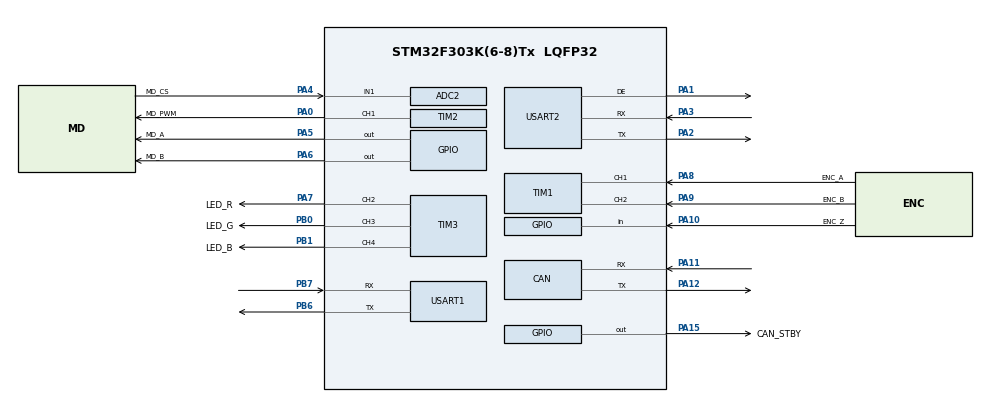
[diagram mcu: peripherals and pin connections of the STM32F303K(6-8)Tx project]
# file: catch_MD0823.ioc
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ADC2.Channel-0\#ChannelRegularConversion=ADC_CHANNEL_1
ADC2.NbrOfConversionFlag=1
ADC2.Offset-0\#ChannelRegularConversion=0
ADC2.OffsetNumber-0\#ChannelRegularConversion=ADC_OFFSET_NONE
ADC2.Rank-0\#ChannelRegularConversion=1
ADC2.SamplingTime-0\#ChannelRegularConversion=ADC_SAMPLETIME_1CYCLE_5
ADC2.SubFamily=STM32F303x8
CAN.CalculateTimeQuantum=2000.0
Mcu.Family=STM32F3
Mcu.Name=STM32F303K(6-8)Tx
Mcu.Package=LQFP32
NVIC.PriorityGroup=NVIC_PRIORITYGROUP_4
PA0.GPIO_Label=MD_PWM
PA0.Signal=S_TIM2_CH1_ETR
PA1.Mode=Hardware Flow Control (RS485)
PA1.Signal=USART2_DE
PA10.GPIO_Label=ENC_Z
PA10.Signal=GPIO_Input
PA11.Mode=Master
PA11.Signal=CAN_RX
PA12.Mode=Master
PA12.Signal=CAN_TX
PA13.Mode=Serial_Wire
PA13.Signal=SYS_JTMS-SWDIO
PA14.Mode=Serial_Wire
PA14.Signal=SYS_JTCK-SWCLK
PA15.GPIO_Label=CAN_STBY
PA15.Signal=GPIO_Output
PA2.Mode=Asynchronous
PA2.Signal=USART2_TX
PA3.Mode=Asynchronous
PA3.Signal=USART2_RX
PA4.GPIO_Label=MD_CS
PA4.Mode=IN1-Single-Ended
PA4.Signal=ADC2_IN1
PA5.GPIO_Label=MD_A
PA5.Signal=GPIO_Output
PA6.GPIO_Label=MD_B
PA6.Signal=GPIO_Output
PA7.GPIO_Label=LED_R
PA7.Signal=S_TIM3_CH2
PA8.GPIO_Label=ENC_A
PA8.Signal=S_TIM1_CH1
PA9.GPIO_Label=ENC_B
PA9.Signal=S_TIM1_CH2
PB0.GPIO_Label=LED_G
PB0.Signal=S_TIM3_CH3
PB1.GPIO_Label=LED_B
PB1.Signal=S_TIM3_CH4
PB6.Mode=Asynchronous
PB6.Signal=USART1_TX
PB7.Mode=Asynchronous
PB7.Signal=USART1_RX
ProjectManager.HeapSize=0x200
ProjectManager.StackSize=0x400
ProjectManager.TargetToolchain=SW4STM32
RCC.AHBFreq_Value=8000000
RCC.APB1Freq_Value=8000000
RCC.APB2Freq_Value=8000000
RCC.CortexFreq_Value=8000000
RCC.HSE_VALUE=8000000
RCC.HSI_VALUE=8000000
RCC.PLLMUL=RCC_PLL_MUL4
RCC.SYSCLKFreq_VALUE=8000000
SH.S_TIM1_CH1.0=TIM1_CH1,Encoder_Interface
SH.S_TIM1_CH2.0=TIM1_CH2,Encoder_Interface
SH.S_TIM2_CH1_ETR.0=TIM2_CH1,PWM Generation1 CH1
SH.S_TIM3_CH2.0=TIM3_CH2,PWM Generation2 CH2
SH.S_TIM3_CH3.0=TIM3_CH3,PWM Generation3 CH3
SH.S_TIM3_CH4.0=TIM3_CH4,PWM Generation4 CH4
TIM2.Channel-PWM\ Generation1\ CH1=TIM_CHANNEL_1
TIM2.Period=999
TIM2.Prescaler=126
TIM3.Channel-PWM\ Generation2\ CH2=TIM_CHANNEL_2
TIM3.Channel-PWM\ Generation3\ CH3=TIM_CHANNEL_3
TIM3.Channel-PWM\ Generation4\ CH4=TIM_CHANNEL_4
USART1.VirtualMode-Asynchronous=VM_ASYNC
USART2.VirtualMode-Asynchronous=VM_ASYNC
USART2.VirtualMode-Hardware\ Flow\ Control\ (RS485)=VM_ASYNC
VP_TIM17_VS_ClockSourceINT.Mode=Enable_Timer
board=custom

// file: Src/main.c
/* USER CODE BEGIN Header */
/**
  ******************************************************************************
  * @file           : main.c
  * @brief          : Main program body
  ******************************************************************************
  * @attention
  *
  * <h2><center>&copy; Copyright (c) 2019 STMicroelectronics.
  * All rights reserved.</center></h2>
  *
  * This software component is licensed by ST under BSD 3-Clause license,
  * the "License"; You may not use this file except in compliance with the
  * License. You may obtain a copy of the License at:
  *                        opensource.org/licenses/BSD-3-Clause
  *
  ******************************************************************************
  */
/* USER CODE END Header */

#include "main.h"

/* USER CODE BEGIN Includes */
#include "struct.h"
#include "motor.h"
#include "encoder.h"
#include "robotstate.h"

/* USER CODE END Includes */

ADC_HandleTypeDef hadc2;

CAN_HandleTypeDef hcan;

TIM_HandleTypeDef htim1;
TIM_HandleTypeDef htim2;
TIM_HandleTypeDef htim3;
TIM_HandleTypeDef htim17;

UART_HandleTypeDef huart1;
UART_HandleTypeDef huart2;

/* USER CODE BEGIN PV */
static char s[255] = {'\0'};
int pwm_result = 0;

//CAN data storage
uint8_t tx[8]; //data which send to "main"
uint8_t rx[8]; //data which receive from "main"
CAN_FilterTypeDef sFilterConfig1;
CAN_TxHeaderTypeDef pHeader1;
CAN_RxHeaderTypeDef pHeader2;
/* USER CODE END PV */

void SystemClock_Config(void);
static void MX_GPIO_Init(void);
static void MX_ADC2_Init(void);
static void MX_CAN_Init(void);
static void MX_TIM1_Init(void);
static void MX_TIM2_Init(void);
static void MX_TIM3_Init(void);
static void MX_TIM17_Init(void);
static void MX_USART1_UART_Init(void);
static void MX_USART2_UART_Init(void);

int main(void)
{

  /* MCU Configuration--------------------------------------------------------*/

  /* Reset of all peripherals, Initializes the Flash interface and the Systick. */
  HAL_Init();

  /* Configure the system clock */
  SystemClock_Config();

  /* Initialize all configured peripherals */
  MX_GPIO_Init();
  MX_ADC2_Init();
  MX_CAN_Init();
  MX_TIM1_Init();
  MX_TIM2_Init();
  MX_TIM3_Init();
  MX_TIM17_Init();
  MX_USART1_UART_Init();
  MX_USART2_UART_Init();
  /* USER CODE BEGIN 2 */
  CoordinateEnable();

  EncEnable();

  HAL_Delay(300);

  pwm_result = TestPos(0.8f);

  HAL_Delay(2000);

  pwm_result = TestPos(-0.8f);

  HAL_Delay(2000);

  CoordinateDisable();
  HAL_Delay(500);

//  CoordinateEnable();
  HAL_TIM_PWM_Start(&htim3,TIM_CHANNEL_2 );

  /* USER CODE END 2 */

  /* Infinite loop */
  /* USER CODE BEGIN WHILE */
  while (1)
  {

	  __HAL_TIM_SET_COMPARE(&htim3, TIM_CHANNEL_2, 	800);
	  HAL_Delay(500);
	  __HAL_TIM_SET_COMPARE(&htim3, TIM_CHANNEL_2, 	200);
	  HAL_Delay(500);

	  /*
	  HAL_GPIO_WritePin(GPIOA, GPIO_PIN_7, GPIO_PIN_SET);
	  HAL_GPIO_WritePin(GPIOB, GPIO_PIN_0, GPIO_PIN_SET);
	  HAL_GPIO_WritePin(GPIOB, GPIO_PIN_1, GPIO_PIN_SET);

//	  HAL_GPIO_WritePin(MOTOR_R_1_PORT, MOTOR_R_1_PIN, GPIO_PIN_RESET);
//	  HAL_GPIO_WritePin(MOTOR_R_2_PORT, MOTOR_R_2_PIN, GPIO_PIN_SET);

	  HAL_Delay(500);
	  HAL_GPIO_WritePin(GPIOA, GPIO_PIN_7, GPIO_PIN_RESET);
	  HAL_GPIO_WritePin(GPIOB, GPIO_PIN_0, GPIO_PIN_RESET);
	  HAL_GPIO_WritePin(GPIOB, GPIO_PIN_1, GPIO_PIN_RESET);

	  HAL_GPIO_WritePin(MOTOR_R_1_PORT, MOTOR_R_1_PIN, GPIO_PIN_SET);
      HAL_GPIO_WritePin(MOTOR_R_2_PORT, MOTOR_R_2_PIN, GPIO_PIN_RESET);

	  HAL_Delay(500);
	  */

	  static int16_t enc1_buf = 0;
	  //receive data(instruction) from "main"
	  if (HAL_CAN_GetRxFifoFillLevel(&hcan,CAN_RX_FIFO0) != 0U)
	  {
	    if (HAL_CAN_GetRxMessage(&hcan, CAN_RX_FIFO0, &pHeader2, rx) != HAL_OK)
	    {
	  	  Error_Handler();
	    }
	  }
//	  rx[0],rx[1]... use for encoder
	  //get measurement data
	  EncGetData(&enc1_buf);
//	  enc1_buf = -10;
	  sprintf(s, "Enc1: %d \r\n", (int)enc1_buf);
	  HAL_UART_Transmit(&huart2,(uint8_t *)s, strlen(s), 100);
	  //send data to "main"
	  tx[0] = (int)enc1_buf;
	  if (HAL_CAN_AddTxMessage(&hcan, &pHeader1, tx, (uint32_t *)CAN_TX_MAILBOX0) != HAL_OK)
	  {
	    Error_Handler();
	  }
	  HAL_Delay(500);

    /* USER CODE END WHILE */

  }
}

void SystemClock_Config(void)
{
  RCC_OscInitTypeDef RCC_OscInitStruct = {0};
  RCC_ClkInitTypeDef RCC_ClkInitStruct = {0};
  RCC_PeriphCLKInitTypeDef PeriphClkInit = {0};

  /** Initializes the CPU, AHB and APB busses clocks
  */
  RCC_OscInitStruct.OscillatorType = RCC_OSCILLATORTYPE_HSI;
  RCC_OscInitStruct.HSIState = RCC_HSI_ON;
  RCC_OscInitStruct.HSICalibrationValue = RCC_HSICALIBRATION_DEFAULT;
  RCC_OscInitStruct.PLL.PLLState = RCC_PLL_ON;
  RCC_OscInitStruct.PLL.PLLSource = RCC_PLLSOURCE_HSI;
  RCC_OscInitStruct.PLL.PLLMUL = RCC_PLL_MUL8;
  if (HAL_RCC_OscConfig(&RCC_OscInitStruct) != HAL_OK)
  {
    Error_Handler();
  }
  /** Initializes the CPU, AHB and APB busses clocks
  */
  RCC_ClkInitStruct.ClockType = RCC_CLOCKTYPE_HCLK|RCC_CLOCKTYPE_SYSCLK
                              |RCC_CLOCKTYPE_PCLK1|RCC_CLOCKTYPE_PCLK2;
  RCC_ClkInitStruct.SYSCLKSource = RCC_SYSCLKSOURCE_PLLCLK;
  RCC_ClkInitStruct.AHBCLKDivider = RCC_SYSCLK_DIV1;
  RCC_ClkInitStruct.APB1CLKDivider = RCC_HCLK_DIV1;
  RCC_ClkInitStruct.APB2CLKDivider = RCC_HCLK_DIV1;

  if (HAL_RCC_ClockConfig(&RCC_ClkInitStruct, FLASH_LATENCY_1) != HAL_OK)
  {
    Error_Handler();
  }
  PeriphClkInit.PeriphClockSelection = RCC_PERIPHCLK_USART1|RCC_PERIPHCLK_TIM1
                              |RCC_PERIPHCLK_ADC12;
  PeriphClkInit.Usart1ClockSelection = RCC_USART1CLKSOURCE_PCLK1;
  PeriphClkInit.Adc12ClockSelection = RCC_ADC12PLLCLK_DIV1;
  PeriphClkInit.Tim1ClockSelection = RCC_TIM1CLK_HCLK;
  if (HAL_RCCEx_PeriphCLKConfig(&PeriphClkInit) != HAL_OK)
  {
    Error_Handler();
  }
}

static void MX_ADC2_Init(void)
{

  ADC_ChannelConfTypeDef sConfig = {0};

  /** Common config
  */
  hadc2.Instance = ADC2;
  hadc2.Init.ClockPrescaler = ADC_CLOCK_ASYNC_DIV1;
  hadc2.Init.Resolution = ADC_RESOLUTION_12B;
  hadc2.Init.ScanConvMode = ADC_SCAN_DISABLE;
  hadc2.Init.ContinuousConvMode = DISABLE;
  hadc2.Init.DiscontinuousConvMode = DISABLE;
  hadc2.Init.ExternalTrigConvEdge = ADC_EXTERNALTRIGCONVEDGE_NONE;
  hadc2.Init.ExternalTrigConv = ADC_SOFTWARE_START;
  hadc2.Init.DataAlign = ADC_DATAALIGN_RIGHT;
  hadc2.Init.NbrOfConversion = 1;
  hadc2.Init.DMAContinuousRequests = DISABLE;
  hadc2.Init.EOCSelection = ADC_EOC_SINGLE_CONV;
  hadc2.Init.LowPowerAutoWait = DISABLE;
  hadc2.Init.Overrun = ADC_OVR_DATA_OVERWRITTEN;
  if (HAL_ADC_Init(&hadc2) != HAL_OK)
  {
    Error_Handler();
  }
  /** Configure Regular Channel
  */
  sConfig.Channel = ADC_CHANNEL_1;
  sConfig.Rank = ADC_REGULAR_RANK_1;
  sConfig.SingleDiff = ADC_SINGLE_ENDED;
  sConfig.SamplingTime = ADC_SAMPLETIME_1CYCLE_5;
  sConfig.OffsetNumber = ADC_OFFSET_NONE;
  sConfig.Offset = 0;
  if (HAL_ADC_ConfigChannel(&hadc2, &sConfig) != HAL_OK)
  {
    Error_Handler();
  }

}

static void MX_CAN_Init(void)
{

  hcan.Instance = CAN;
  hcan.Init.Prescaler = 16;
  hcan.Init.Mode = CAN_MODE_NORMAL;
  hcan.Init.SyncJumpWidth = CAN_SJW_1TQ;
  hcan.Init.TimeSeg1 = CAN_BS1_1TQ;
  hcan.Init.TimeSeg2 = CAN_BS2_1TQ;
  hcan.Init.TimeTriggeredMode = DISABLE;
  hcan.Init.AutoBusOff = DISABLE;
  hcan.Init.AutoWakeUp = DISABLE;
  hcan.Init.AutoRetransmission = DISABLE;
  hcan.Init.ReceiveFifoLocked = DISABLE;
  hcan.Init.TransmitFifoPriority = DISABLE;
  if (HAL_CAN_Init(&hcan) != HAL_OK)
  {
    Error_Handler();
  }
  /* USER CODE BEGIN CAN_Init 2 */

  sFilterConfig1.FilterIdHigh = 0x0020;//32(this_slave_stdId=1)**(all_slave_stdId is 1~8)
  sFilterConfig1.FilterIdLow = 0x0000;
  sFilterConfig1.FilterMaskIdHigh = 0xFFE0;//"stdId=1" only accept
  sFilterConfig1.FilterMaskIdLow = 0x0004; //CAN_ID_STD accept
  sFilterConfig1.FilterMode = CAN_FILTERMODE_IDMASK;
  sFilterConfig1.FilterScale = CAN_FILTERSCALE_32BIT;
  sFilterConfig1.FilterFIFOAssignment = 0;
  sFilterConfig1.FilterActivation = ENABLE;
  if (HAL_CAN_ConfigFilter(&hcan, &sFilterConfig1) != HAL_OK)
    {
      // Filter configuration Error
      Error_Handler();
    }
  pHeader1.IDE = CAN_ID_STD;//NOT extend
  pHeader1.RTR = CAN_RTR_DATA;
  pHeader1.StdId = 0x10;//main stdId is 16 **(all main is 16~23)
  pHeader1.ExtId = 0x10;
  pHeader1.DLC = 1;//number of tx data

  /* USER CODE END CAN_Init 2 */

}

static void MX_TIM1_Init(void)
{

  TIM_Encoder_InitTypeDef sConfig = {0};
  TIM_MasterConfigTypeDef sMasterConfig = {0};

  htim1.Instance = TIM1;
  htim1.Init.Prescaler = 0;
  htim1.Init.CounterMode = TIM_COUNTERMODE_UP;
  htim1.Init.Period = 0;
  htim1.Init.ClockDivision = TIM_CLOCKDIVISION_DIV1;
  htim1.Init.RepetitionCounter = 0;
  htim1.Init.AutoReloadPreload = TIM_AUTORELOAD_PRELOAD_DISABLE;
  sConfig.EncoderMode = TIM_ENCODERMODE_TI1;
  sConfig.IC1Polarity = TIM_ICPOLARITY_RISING;
  sConfig.IC1Selection = TIM_ICSELECTION_DIRECTTI;
  sConfig.IC1Prescaler = TIM_ICPSC_DIV1;
  sConfig.IC1Filter = 0;
  sConfig.IC2Polarity = TIM_ICPOLARITY_RISING;
  sConfig.IC2Selection = TIM_ICSELECTION_DIRECTTI;
  sConfig.IC2Prescaler = TIM_ICPSC_DIV1;
  sConfig.IC2Filter = 0;
  if (HAL_TIM_Encoder_Init(&htim1, &sConfig) != HAL_OK)
  {
    Error_Handler();
  }
  sMasterConfig.MasterOutputTrigger = TIM_TRGO_RESET;
  sMasterConfig.MasterOutputTrigger2 = TIM_TRGO2_RESET;
  sMasterConfig.MasterSlaveMode = TIM_MASTERSLAVEMODE_DISABLE;
  if (HAL_TIMEx_MasterConfigSynchronization(&htim1, &sMasterConfig) != HAL_OK)
  {
    Error_Handler();
  }

}

static void MX_TIM2_Init(void)
{

  TIM_MasterConfigTypeDef sMasterConfig = {0};
  TIM_OC_InitTypeDef sConfigOC = {0};

  htim2.Instance = TIM2;
  htim2.Init.Prescaler = 0;
  htim2.Init.CounterMode = TIM_COUNTERMODE_UP;
  htim2.Init.Period = 0;
  htim2.Init.ClockDivision = TIM_CLOCKDIVISION_DIV1;
  htim2.Init.AutoReloadPreload = TIM_AUTORELOAD_PRELOAD_DISABLE;
  if (HAL_TIM_PWM_Init(&htim2) != HAL_OK)
  {
    Error_Handler();
  }
  sMasterConfig.MasterOutputTrigger = TIM_TRGO_RESET;
  sMasterConfig.MasterSlaveMode = TIM_MASTERSLAVEMODE_DISABLE;
  if (HAL_TIMEx_MasterConfigSynchronization(&htim2, &sMasterConfig) != HAL_OK)
  {
    Error_Handler();
  }
  sConfigOC.OCMode = TIM_OCMODE_PWM1;
  sConfigOC.Pulse = 0;
  sConfigOC.OCPolarity = TIM_OCPOLARITY_HIGH;
  sConfigOC.OCFastMode = TIM_OCFAST_DISABLE;
  if (HAL_TIM_PWM_ConfigChannel(&htim2, &sConfigOC, TIM_CHANNEL_1) != HAL_OK)
  {
    Error_Handler();
  }
  HAL_TIM_MspPostInit(&htim2);

}

static void MX_TIM3_Init(void)
{

  TIM_MasterConfigTypeDef sMasterConfig = {0};
  TIM_OC_InitTypeDef sConfigOC = {0};

  htim3.Instance = TIM3;
  htim3.Init.Prescaler = 0;
  htim3.Init.CounterMode = TIM_COUNTERMODE_UP;
  htim3.Init.Period = 0;
  htim3.Init.ClockDivision = TIM_CLOCKDIVISION_DIV1;
  htim3.Init.AutoReloadPreload = TIM_AUTORELOAD_PRELOAD_DISABLE;
  if (HAL_TIM_PWM_Init(&htim3) != HAL_OK)
  {
    Error_Handler();
  }
  sMasterConfig.MasterOutputTrigger = TIM_TRGO_RESET;
  sMasterConfig.MasterSlaveMode = TIM_MASTERSLAVEMODE_DISABLE;
  if (HAL_TIMEx_MasterConfigSynchronization(&htim3, &sMasterConfig) != HAL_OK)
  {
    Error_Handler();
  }
  sConfigOC.OCMode = TIM_OCMODE_PWM1;
  sConfigOC.Pulse = 0;
  sConfigOC.OCPolarity = TIM_OCPOLARITY_HIGH;
  sConfigOC.OCFastMode = TIM_OCFAST_DISABLE;
  if (HAL_TIM_PWM_ConfigChannel(&htim3, &sConfigOC, TIM_CHANNEL_2) != HAL_OK)
  {
    Error_Handler();
  }
  if (HAL_TIM_PWM_ConfigChannel(&htim3, &sConfigOC, TIM_CHANNEL_3) != HAL_OK)
  {
    Error_Handler();
  }
  if (HAL_TIM_PWM_ConfigChannel(&htim3, &sConfigOC, TIM_CHANNEL_4) != HAL_OK)
  {
    Error_Handler();
  }
  HAL_TIM_MspPostInit(&htim3);

}

static void MX_TIM17_Init(void)
{

  htim17.Instance = TIM17;
  htim17.Init.Prescaler = 0;
  htim17.Init.CounterMode = TIM_COUNTERMODE_UP;
  htim17.Init.Period = 0;
  htim17.Init.ClockDivision = TIM_CLOCKDIVISION_DIV1;
  htim17.Init.RepetitionCounter = 0;
  htim17.Init.AutoReloadPreload = TIM_AUTORELOAD_PRELOAD_DISABLE;
  if (HAL_TIM_Base_Init(&htim17) != HAL_OK)
  {
    Error_Handler();
  }

}

static void MX_USART1_UART_Init(void)
{

  huart1.Instance = USART1;
  huart1.Init.BaudRate = 38400;
  huart1.Init.WordLength = UART_WORDLENGTH_8B;
  huart1.Init.StopBits = UART_STOPBITS_1;
  huart1.Init.Parity = UART_PARITY_NONE;
  huart1.Init.Mode = UART_MODE_TX_RX;
  huart1.Init.HwFlowCtl = UART_HWCONTROL_NONE;
  huart1.Init.OverSampling = UART_OVERSAMPLING_16;
  huart1.Init.OneBitSampling = UART_ONE_BIT_SAMPLE_DISABLE;
  huart1.AdvancedInit.AdvFeatureInit = UART_ADVFEATURE_NO_INIT;
  if (HAL_UART_Init(&huart1) != HAL_OK)
  {
    Error_Handler();
  }

}

static void MX_USART2_UART_Init(void)
{

  huart2.Instance = USART2;
  huart2.Init.BaudRate = 38400;
  huart2.Init.WordLength = UART_WORDLENGTH_8B;
  huart2.Init.StopBits = UART_STOPBITS_1;
  huart2.Init.Parity = UART_PARITY_NONE;
  huart2.Init.Mode = UART_MODE_TX_RX;
  huart2.Init.HwFlowCtl = UART_HWCONTROL_NONE;
  huart2.Init.OverSampling = UART_OVERSAMPLING_16;
  huart2.Init.OneBitSampling = UART_ONE_BIT_SAMPLE_DISABLE;
  huart2.AdvancedInit.AdvFeatureInit = UART_ADVFEATURE_NO_INIT;
  if (HAL_RS485Ex_Init(&huart2, UART_DE_POLARITY_HIGH, 0, 0) != HAL_OK)
  {
    Error_Handler();
  }

}

static void MX_GPIO_Init(void)
{
  GPIO_InitTypeDef GPIO_InitStruct = {0};

  /* GPIO Ports Clock Enable */
  __HAL_RCC_GPIOA_CLK_ENABLE();
  __HAL_RCC_GPIOB_CLK_ENABLE();

  /*Configure GPIO pin Output Level */
  HAL_GPIO_WritePin(GPIOA, MD_A_Pin|MD_B_Pin|CAN_STBY_Pin, GPIO_PIN_RESET);

  /*Configure GPIO pins : MD_A_Pin MD_B_Pin CAN_STBY_Pin */
  GPIO_InitStruct.Pin = MD_A_Pin|MD_B_Pin|CAN_STBY_Pin;
  GPIO_InitStruct.Mode = GPIO_MODE_OUTPUT_PP;
  GPIO_InitStruct.Pull = GPIO_NOPULL;
  GPIO_InitStruct.Speed = GPIO_SPEED_FREQ_LOW;
  HAL_GPIO_Init(GPIOA, &GPIO_InitStruct);

  /*Configure GPIO pin : ENC_Z_Pin */
  GPIO_InitStruct.Pin = ENC_Z_Pin;
  GPIO_InitStruct.Mode = GPIO_MODE_INPUT;
  GPIO_InitStruct.Pull = GPIO_NOPULL;
  HAL_GPIO_Init(ENC_Z_GPIO_Port, &GPIO_InitStruct);

}

void Error_Handler(void)
{
}

/************************ (C) COPYRIGHT STMicroelectronics *****END OF FILE****/
